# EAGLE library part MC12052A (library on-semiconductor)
1.1 GHZ Suiper Low Power Dual Modulus Prescaler Source:http://motorola.com/sps .. MC12052A.pdf

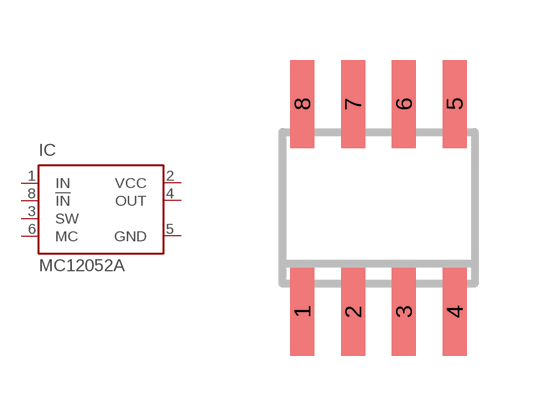
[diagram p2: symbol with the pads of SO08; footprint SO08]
Designator prefix IC

## MC12052AD (OC_FARNELL: unknown; OC_NEWARK: unknown)  [SO08]
1  IN  in
2  VCC  pwr
3  SW  in
4  OUT  out
5  GND  pwr
6  MC  in
8  !IN  in

## Footprint SO08 (pad centres in mm)
Small Outline Package 8 NS Package M08A
smd 0.6 x 2.2: 1 -1.905,-2.6; 2 -0.635,-2.6; 3 0.635,-2.6; 4 1.905,-2.6; 5 1.905,2.6; 6 0.635,2.6; 7 -0.635,2.6; 8 -1.905,2.6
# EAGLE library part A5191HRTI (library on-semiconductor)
HART Modem Single-chip, half-duplex 1200 bits per second FSK modem Auto generated by make-symbol-device-package-bsdl.ulp Rev. 35 Source:OnSemi A5191HRT HART Modem Data Sheet.pdf

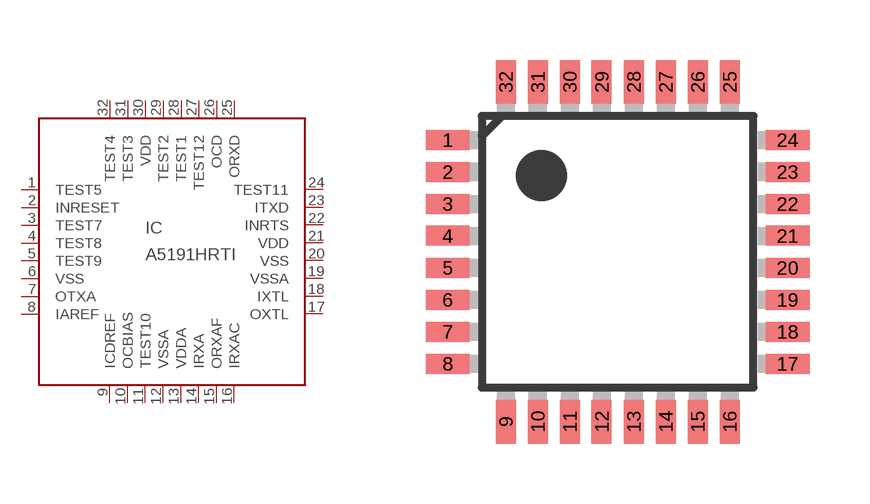
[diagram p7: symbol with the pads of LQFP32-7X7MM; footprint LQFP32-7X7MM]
Designator prefix IC

## A5191HRTI (MPN: A5191HRTLG-XTD; OC_FARNELL: unknown; OC_NEWARK: 03P1166)  [LQFP32-7X7MM]
1  TEST5  in
2  INRESET  in
3  TEST7  in
4  TEST8  in
5  TEST9  in
6  VSS  pwr
7  OTXA  out
8  IAREF  in
9  ICDREF  in
10  OCBIAS  out
11  TEST10  in
12  VSSA  pwr
13  VDDA  pwr
14  IRXA  in
15  ORXAF  out
16  IRXAC  in
17  OXTL  out
18  IXTL  in
19  VSSA  pwr
20  VSS  pwr
21  VDD  pwr
22  INRTS  in
23  ITXD  in
24  TEST11  nc
25  ORXD  out
26  OCD  out
27  TEST12  nc
28  TEST1  in
29  TEST2  nc
30  VDD  pwr
31  TEST3  nc
32  TEST4  nc

## Footprint LQFP32-7X7MM (pad centres in mm)
LQFP 32 7 x 7 mm Auto generated by make-symbol-device-package-bsdl.ulp Rev. 35 Source:OnSemi A5191HRT HART Modem Data Sheet.pdf
smd 1.1 x 0.5: 1 -4.25,2.8; 2 -4.25,2; 3 -4.25,1.2; 4 -4.25,0.4; 5 -4.25,-0.4; 6 -4.25,-1.2; 7 -4.25,-2; 8 -4.25,-2.8; 17 4.25,-2.8; 18 4.25,-2; 19 4.25,-1.2; 20 4.25,-0.4; 21 4.25,0.4; 22 4.25,1.2; 23 4.25,2; 24 4.25,2.8
smd 0.5 x 1.1: 9 -2.8,-4.25; 10 -2,-4.25; 11 -1.2,-4.25; 12 -0.4,-4.25; 13 0.4,-4.25; 14 1.2,-4.25; 15 2,-4.25; 16 2.8,-4.25; 25 2.8,4.25; 26 2,4.25; 27 1.2,4.25; 28 0.4,4.25; 29 -0.4,4.25; 30 -1.2,4.25; 31 -2,4.25; 32 -2.8,4.25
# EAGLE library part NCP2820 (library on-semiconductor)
2.65 W Filterless Class-D Audio Power Amplifier Source: Data sheet

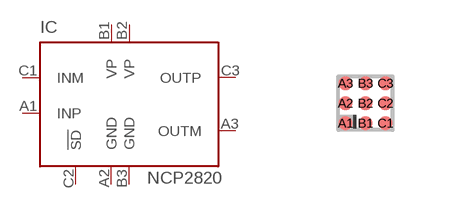
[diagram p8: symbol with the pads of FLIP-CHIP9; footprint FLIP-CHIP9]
Designator prefix IC

## NCP2820  [FLIP-CHIP9]
A1  INP  in
A2  GND  pwr
A3  OUTM  out
B1  VP  pwr
B2  VP  pwr
B3  GND  pwr
C1  INM  in
C2  !SD  in
C3  OUTP  out

## Footprint FLIP-CHIP9 (pad centres in mm)
9 PIN FLIP?CHIP CASE 499AL?01 ISSUE O BGA 9 pol. Source: Data sheet
smd 0.34 x 0.34: A1 -0.5,-0.5; A2 -0.5,0; A3 -0.5,0.5; B1 0,-0.5; B2 0,0; B3 0,0.5; C1 0.5,-0.5; C2 0.5,0; C3 0.5,0.5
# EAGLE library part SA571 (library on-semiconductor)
Versatile low cost dual gain control circuit Source: Data sheet

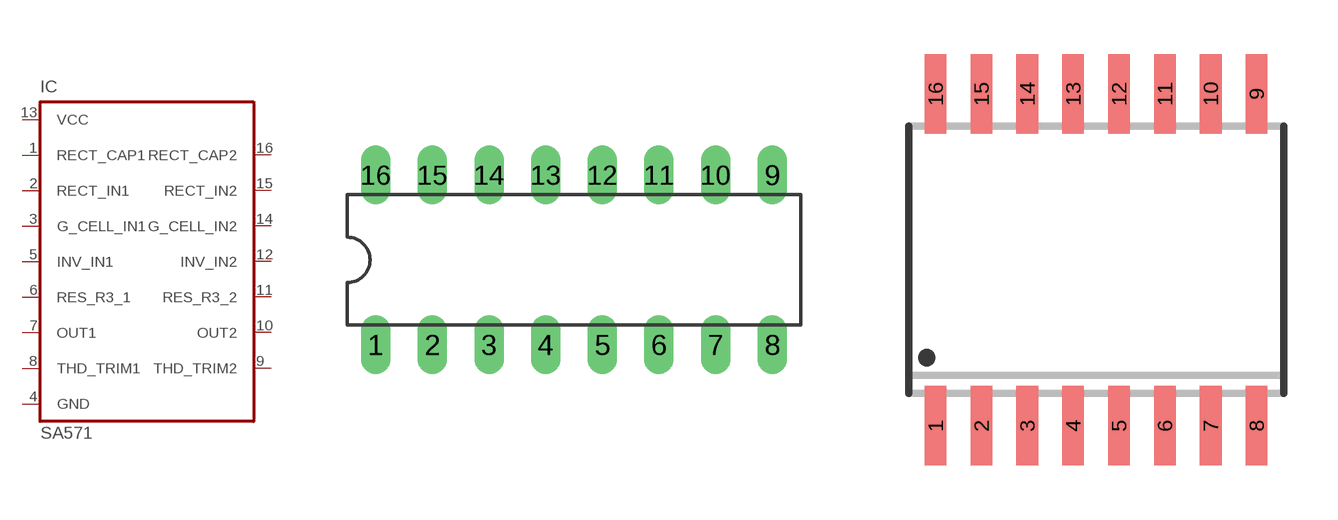
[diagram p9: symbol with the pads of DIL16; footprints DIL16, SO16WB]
Designator prefix IC

## SA571N  [DIL16]
1  RECT_CAP1  pas
2  RECT_IN1  in
3  G_CELL_IN1  in
4  GND  pwr
5  INV_IN1  in
6  RES_R3_1  in
7  OUT1  out
8  THD_TRIM1  in
9  THD_TRIM2  in
10  OUT2  out
11  RES_R3_2  in
12  INV_IN2  in
13  VCC  pwr
14  G_CELL_IN2  in
15  RECT_IN2  in
16  RECT_CAP2  pas

## SA571D  [SO16WB]
Pads as for DIL16

## Footprint DIL16 (pad centres in mm)
Dual In Line Package
drill 0.813 long: 1 -8.89,-3.81; 2 -6.35,-3.81; 3 -3.81,-3.81; 4 -1.27,-3.81; 5 1.27,-3.81; 6 3.81,-3.81; 7 6.35,-3.81; 8 8.89,-3.81; 9 8.89,3.81; 10 6.35,3.81; 11 3.81,3.81; 12 1.27,3.81; 13 -1.27,3.81; 14 -3.81,3.81; 15 -6.35,3.81; 16 -8.89,3.81

## Footprint SO16WB (pad centres in mm)
SOIC-16WB D SUFFIX CASE 751G-03 ISSUE C Source: Data sheet
smd 0.6 x 2.2: 1 -4.445,-4.6; 2 -3.175,-4.6; 3 -1.905,-4.6; 4 -0.635,-4.6; 5 0.635,-4.6; 6 1.905,-4.6; 7 3.175,-4.6; 8 4.445,-4.6; 9 4.445,4.6; 10 3.175,4.6; 11 1.905,4.6; 12 0.635,4.6; 13 -0.635,4.6; 14 -1.905,4.6; 15 -3.175,4.6; 16 -4.445,4.6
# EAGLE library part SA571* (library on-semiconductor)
Versatile low cost dual gain control circuit Source: Data sheet

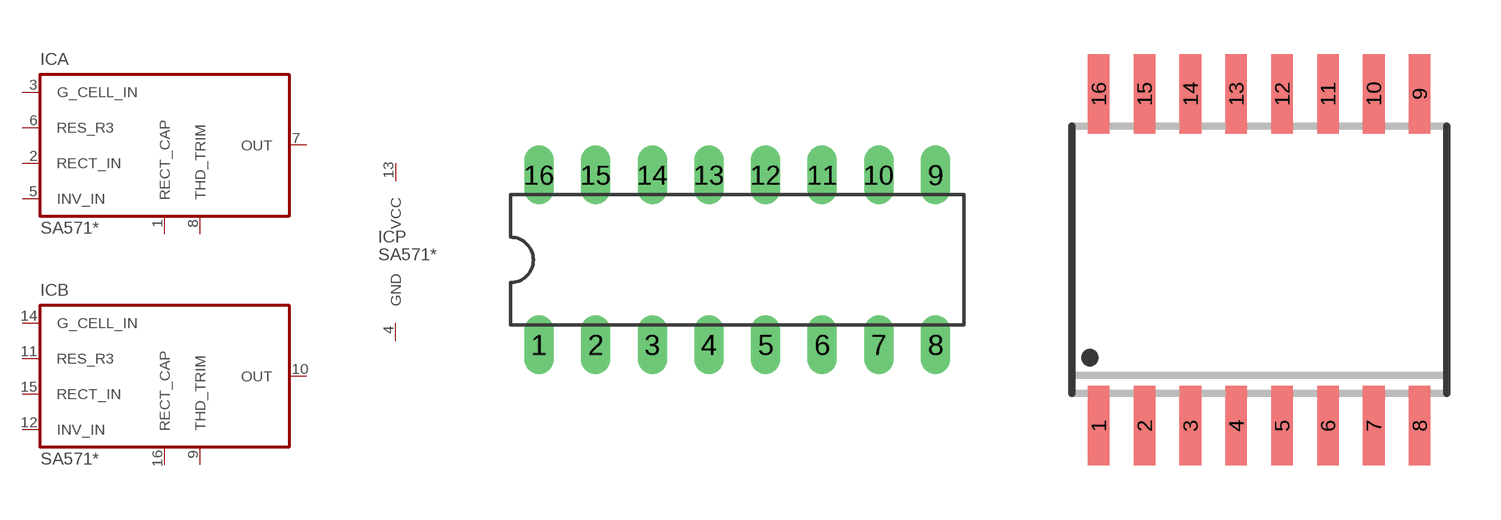
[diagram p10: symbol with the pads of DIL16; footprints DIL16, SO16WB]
Designator prefix IC; gates A=SA571-G B=SA571-G P=PWR2

## SA571N  [DIL16]
1  A:RECT_CAP  pas
2  A:RECT_IN  in
3  A:G_CELL_IN  in
4  P:GND  pwr
5  A:INV_IN  in
6  A:RES_R3  in
7  A:OUT  out
8  A:THD_TRIM  in
9  B:THD_TRIM  in
10  B:OUT  out
11  B:RES_R3  in
12  B:INV_IN  in
13  P:VCC  pwr
14  B:G_CELL_IN  in
15  B:RECT_IN  in
16  B:RECT_CAP  pas

## SA571D  [SO16WB]
Pads as for DIL16

## Footprint DIL16 (pad centres in mm)
Dual In Line Package
drill 0.813 long: 1 -8.89,-3.81; 2 -6.35,-3.81; 3 -3.81,-3.81; 4 -1.27,-3.81; 5 1.27,-3.81; 6 3.81,-3.81; 7 6.35,-3.81; 8 8.89,-3.81; 9 8.89,3.81; 10 6.35,3.81; 11 3.81,3.81; 12 1.27,3.81; 13 -1.27,3.81; 14 -3.81,3.81; 15 -6.35,3.81; 16 -8.89,3.81

## Footprint SO16WB (pad centres in mm)
SOIC-16WB D SUFFIX CASE 751G-03 ISSUE C Source: Data sheet
smd 0.6 x 2.2: 1 -4.445,-4.6; 2 -3.175,-4.6; 3 -1.905,-4.6; 4 -0.635,-4.6; 5 0.635,-4.6; 6 1.905,-4.6; 7 3.175,-4.6; 8 4.445,-4.6; 9 4.445,4.6; 10 3.175,4.6; 11 1.905,4.6; 12 0.635,4.6; 13 -0.635,4.6; 14 -1.905,4.6; 15 -3.175,4.6; 16 -4.445,4.6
